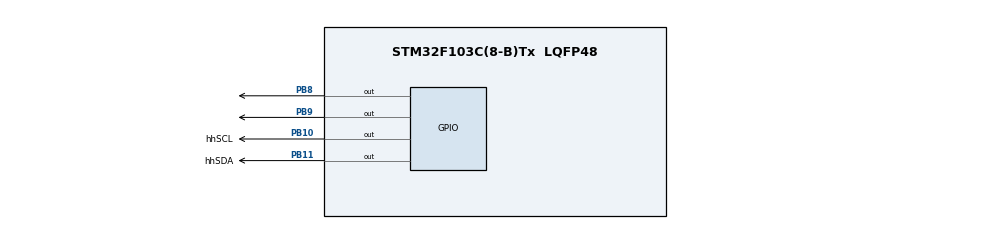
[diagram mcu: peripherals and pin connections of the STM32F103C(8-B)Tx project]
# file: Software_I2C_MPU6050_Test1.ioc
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Mcu.Family=STM32F1
Mcu.Name=STM32F103C(8-B)Tx
Mcu.Package=LQFP48
NVIC.PriorityGroup=NVIC_PRIORITYGROUP_4
PA13.Mode=Serial_Wire
PA13.Signal=SYS_JTMS-SWDIO
PA14.Mode=Serial_Wire
PA14.Signal=SYS_JTCK-SWCLK
PB10.GPIO_Label=hhSCL
PB10.GPIO_ModeDefaultOutputPP=GPIO_MODE_OUTPUT_OD
PB10.GPIO_PuPd=GPIO_NOPULL
PB10.GPIO_Speed=GPIO_SPEED_FREQ_HIGH
PB10.PinState=GPIO_PIN_SET
PB10.Signal=GPIO_Output
PB11.GPIO_Label=hhSDA
PB11.GPIO_ModeDefaultOutputPP=GPIO_MODE_OUTPUT_OD
PB11.GPIO_PuPd=GPIO_NOPULL
PB11.GPIO_Speed=GPIO_SPEED_FREQ_HIGH
PB11.PinState=GPIO_PIN_SET
PB11.Signal=GPIO_Output
PB8.GPIO_ModeDefaultOutputPP=GPIO_MODE_OUTPUT_OD
PB8.GPIO_PuPd=GPIO_NOPULL
PB8.PinState=GPIO_PIN_SET
PB8.Signal=GPIO_Output
PB9.GPIO_ModeDefaultOutputPP=GPIO_MODE_OUTPUT_OD
PB9.GPIO_PuPd=GPIO_NOPULL
PB9.PinState=GPIO_PIN_SET
PB9.Signal=GPIO_Output
PD0-OSC_IN.Mode=HSE-External-Oscillator
PD0-OSC_IN.Signal=RCC_OSC_IN
PD1-OSC_OUT.Mode=HSE-External-Oscillator
PD1-OSC_OUT.Signal=RCC_OSC_OUT
ProjectManager.HeapSize=0x200
ProjectManager.StackSize=0x400
ProjectManager.TargetToolchain=CMake
RCC.AHBFreq_Value=72000000
RCC.APB1CLKDivider=RCC_HCLK_DIV2
RCC.APB1Freq_Value=36000000
RCC.APB1TimFreq_Value=72000000
RCC.APB2Freq_Value=72000000
RCC.APB2TimFreq_Value=72000000
RCC.HCLKFreq_Value=72000000
RCC.PLLMUL=RCC_PLL_MUL9
RCC.PLLSourceVirtual=RCC_PLLSOURCE_HSE
RCC.SYSCLKFreq_VALUE=72000000
RCC.SYSCLKSource=RCC_SYSCLKSOURCE_PLLCLK
RCC.USBFreq_Value=72000000
board=custom

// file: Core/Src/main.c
/* USER CODE BEGIN Header */
/**
  ******************************************************************************
  * @file           : main.c
  * @brief          : Main program body
  ******************************************************************************
  * @attention
  *
  * Copyright (c) 2026 STMicroelectronics.
  * All rights reserved.
  *
  * This software is licensed under terms that can be found in the LICENSE file
  * in the root directory of this software component.
  * If no LICENSE file comes with this software, it is provided AS-IS.
  *
  ******************************************************************************
  */
/* USER CODE END Header */
#include "main.h"

void SystemClock_Config(void);
static void MX_GPIO_Init(void);

int main(void)
{

  /* MCU Configuration--------------------------------------------------------*/

  /* Reset of all peripherals, Initializes the Flash interface and the Systick. */
  HAL_Init();

  /* Configure the system clock */
  SystemClock_Config();

  /* Initialize all configured peripherals */
  MX_GPIO_Init();

  /* Infinite loop */
  while (1)
  {

  }
}

void SystemClock_Config(void)
{
  RCC_OscInitTypeDef RCC_OscInitStruct = {0};
  RCC_ClkInitTypeDef RCC_ClkInitStruct = {0};

  /** Initializes the RCC Oscillators according to the specified parameters
  * in the RCC_OscInitTypeDef structure.
  */
  RCC_OscInitStruct.OscillatorType = RCC_OSCILLATORTYPE_HSI;
  RCC_OscInitStruct.HSIState = RCC_HSI_ON;
  RCC_OscInitStruct.HSICalibrationValue = RCC_HSICALIBRATION_DEFAULT;
  RCC_OscInitStruct.PLL.PLLState = RCC_PLL_NONE;
  if (HAL_RCC_OscConfig(&RCC_OscInitStruct) != HAL_OK)
  {
    Error_Handler();
  }

  /** Initializes the CPU, AHB and APB buses clocks
  */
  RCC_ClkInitStruct.ClockType = RCC_CLOCKTYPE_HCLK|RCC_CLOCKTYPE_SYSCLK
                              |RCC_CLOCKTYPE_PCLK1|RCC_CLOCKTYPE_PCLK2;
  RCC_ClkInitStruct.SYSCLKSource = RCC_SYSCLKSOURCE_HSI;
  RCC_ClkInitStruct.AHBCLKDivider = RCC_SYSCLK_DIV1;
  RCC_ClkInitStruct.APB1CLKDivider = RCC_HCLK_DIV1;
  RCC_ClkInitStruct.APB2CLKDivider = RCC_HCLK_DIV1;

  if (HAL_RCC_ClockConfig(&RCC_ClkInitStruct, FLASH_LATENCY_0) != HAL_OK)
  {
    Error_Handler();
  }
}

static void MX_GPIO_Init(void)
{
  GPIO_InitTypeDef GPIO_InitStruct = {0};

  /* GPIO Ports Clock Enable */
  __HAL_RCC_GPIOB_CLK_ENABLE();
  __HAL_RCC_GPIOA_CLK_ENABLE();

  /*Configure GPIO pin Output Level */
  HAL_GPIO_WritePin(GPIOB, hhSCL_Pin|hhSDA_Pin|GPIO_PIN_8|GPIO_PIN_9, GPIO_PIN_SET);

  /*Configure GPIO pins : hhSCL_Pin hhSDA_Pin */
  GPIO_InitStruct.Pin = hhSCL_Pin|hhSDA_Pin;
  GPIO_InitStruct.Mode = GPIO_MODE_OUTPUT_OD;
  GPIO_InitStruct.Pull = GPIO_NOPULL;
  GPIO_InitStruct.Speed = GPIO_SPEED_FREQ_HIGH;
  HAL_GPIO_Init(GPIOB, &GPIO_InitStruct);

  /*Configure GPIO pins : PB8 PB9 */
  GPIO_InitStruct.Pin = GPIO_PIN_8|GPIO_PIN_9;
  GPIO_InitStruct.Mode = GPIO_MODE_OUTPUT_OD;
  GPIO_InitStruct.Pull = GPIO_NOPULL;
  GPIO_InitStruct.Speed = GPIO_SPEED_FREQ_LOW;
  HAL_GPIO_Init(GPIOB, &GPIO_InitStruct);

}

void Error_Handler(void)
{
  __disable_irq();
  while (1)
  {
  }
}
